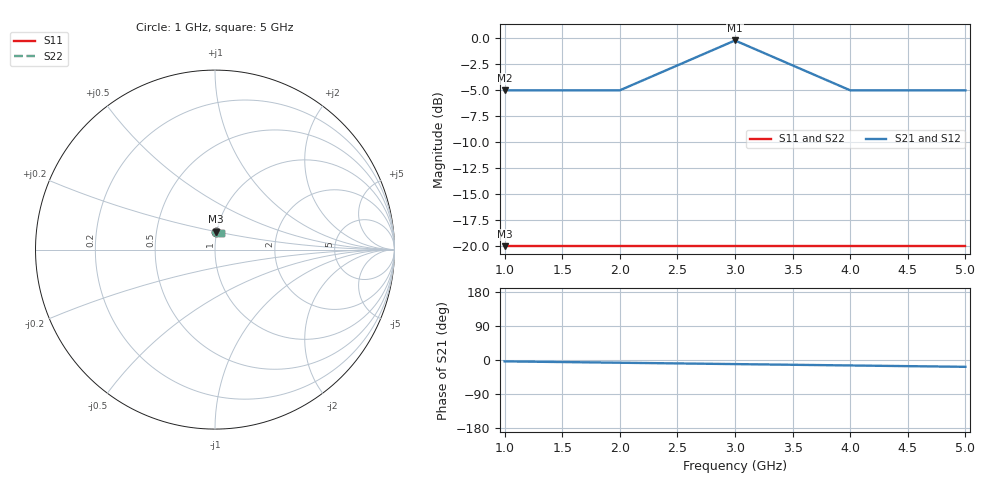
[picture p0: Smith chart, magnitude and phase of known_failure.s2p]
! Frozen feasible-target fixture with a low-loss valley between two controls
! Matrix convention: Sij means output port i due to input port j
# GHZ S RI R 50
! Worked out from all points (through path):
!   5 points, 1 GHz to 5 GHz, reference 50 ohm
!   highest |S21| = -0.20 dB at 3 GHz (marker M1); lowest = -5.0 dB at 1 GHz (marker M2)
!   lowest |S11| = -20.0 dB at 1 GHz (marker M3), VSWR 1.22, Z = 49.6 + j10 ohm
!   |S11| at or under -10 dB: start of sweep to end of sweep
!   |S22| runs from -20.0 to -20.0 dB; largest |S21 - S12| = 0
1  0.00628 0.0998  0.5612 -0.0353  0.5612 -0.0353  0.00628 0.0998
2  0.0125 0.0992  0.5579 -0.0705  0.5579 -0.0705  0.0125 0.0992
3  0.0187 0.0982  0.9599 -0.1831  0.9599 -0.1831  0.0187 0.0982
4  0.0249 0.0969  0.5447 -0.1398  0.5447 -0.1398  0.0249 0.0969
5  0.0309 0.0951  0.5348 -0.1738  0.5348 -0.1738  0.0309 0.0951
